VERSION 5.7 ;
  NOWIREEXTENSIONATPIN ON ;
  DIVIDERCHAR "/" ;
  BUSBITCHARS "[]" ;
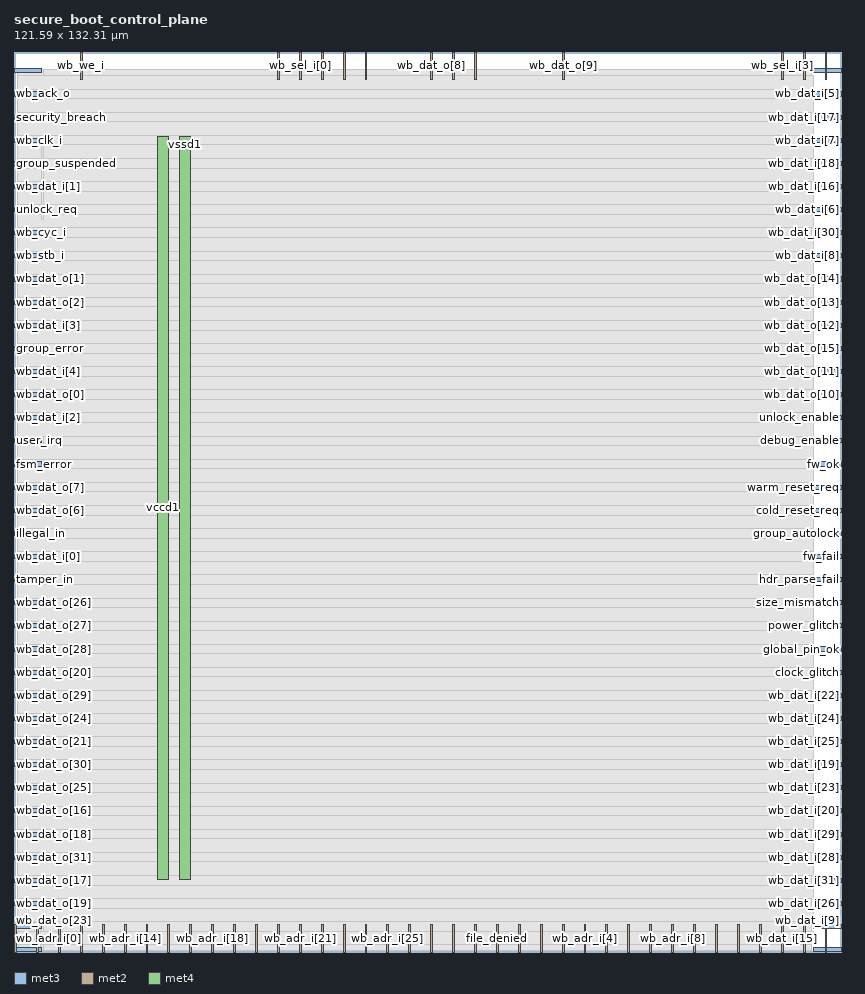
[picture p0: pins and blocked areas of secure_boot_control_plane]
MACRO secure_boot_control_plane
  CLASS BLOCK ;
  FOREIGN secure_boot_control_plane ;
  ORIGIN 0.000 0.000 ;
  SIZE 121.590 BY 132.310 ;
  PIN clock_glitch
    DIRECTION INPUT ;
    USE SIGNAL ;
    ANTENNAGATEAREA 0.631200 ;
    ANTENNADIFFAREA 0.434700 ;
    PORT
      LAYER met3 ;
        RECT 117.590 40.840 121.590 41.440 ;
    END
  END clock_glitch
  PIN cold_reset_req
    DIRECTION INPUT ;
    USE SIGNAL ;
    ANTENNAGATEAREA 0.631200 ;
    ANTENNADIFFAREA 0.434700 ;
    PORT
      LAYER met3 ;
        RECT 117.590 64.640 121.590 65.240 ;
    END
  END cold_reset_req
  PIN debug_enable
    DIRECTION OUTPUT ;
    USE SIGNAL ;
    ANTENNADIFFAREA 0.445500 ;
    PORT
      LAYER met3 ;
        RECT 117.590 74.840 121.590 75.440 ;
    END
  END debug_enable
  PIN file_denied
    DIRECTION INPUT ;
    USE SIGNAL ;
    ANTENNAGATEAREA 0.631200 ;
    ANTENNADIFFAREA 0.434700 ;
    PORT
      LAYER met2 ;
        RECT 70.930 0.000 71.210 4.000 ;
    END
  END file_denied
  PIN fsm_error
    DIRECTION OUTPUT ;
    USE SIGNAL ;
    ANTENNADIFFAREA 0.445500 ;
    PORT
      LAYER met3 ;
        RECT 0.000 71.440 4.000 72.040 ;
    END
  END fsm_error
  PIN fw_fail
    DIRECTION INPUT ;
    USE SIGNAL ;
    ANTENNAGATEAREA 0.631200 ;
    ANTENNADIFFAREA 0.434700 ;
    PORT
      LAYER met3 ;
        RECT 117.590 57.840 121.590 58.440 ;
    END
  END fw_fail
  PIN fw_ok
    DIRECTION INPUT ;
    USE SIGNAL ;
    ANTENNAGATEAREA 0.631200 ;
    ANTENNADIFFAREA 0.434700 ;
    PORT
      LAYER met3 ;
        RECT 117.590 71.440 121.590 72.040 ;
    END
  END fw_ok
  PIN global_pin_ok
    DIRECTION INPUT ;
    USE SIGNAL ;
    ANTENNAGATEAREA 0.631200 ;
    ANTENNADIFFAREA 0.434700 ;
    PORT
      LAYER met3 ;
        RECT 117.590 44.240 121.590 44.840 ;
    END
  END global_pin_ok
  PIN group_autolock
    DIRECTION INPUT ;
    USE SIGNAL ;
    ANTENNAGATEAREA 0.631200 ;
    ANTENNADIFFAREA 0.434700 ;
    PORT
      LAYER met3 ;
        RECT 117.590 61.240 121.590 61.840 ;
    END
  END group_autolock
  PIN group_error
    DIRECTION OUTPUT ;
    USE SIGNAL ;
    ANTENNADIFFAREA 0.445500 ;
    PORT
      LAYER met3 ;
        RECT 0.000 88.440 4.000 89.040 ;
    END
  END group_error
  PIN group_suspended
    DIRECTION OUTPUT ;
    USE SIGNAL ;
    ANTENNADIFFAREA 0.445500 ;
    PORT
      LAYER met3 ;
        RECT 0.000 115.640 4.000 116.240 ;
    END
  END group_suspended
  PIN group_unlocked
    DIRECTION OUTPUT ;
    USE SIGNAL ;
    ANTENNADIFFAREA 0.445500 ;
    PORT
      LAYER met2 ;
        RECT 67.710 0.000 67.990 4.000 ;
    END
  END group_unlocked
  PIN hdr_parse_fail
    DIRECTION INPUT ;
    USE SIGNAL ;
    ANTENNAGATEAREA 0.631200 ;
    ANTENNADIFFAREA 0.434700 ;
    PORT
      LAYER met3 ;
        RECT 117.590 54.440 121.590 55.040 ;
    END
  END hdr_parse_fail
  PIN illegal_in
    DIRECTION INPUT ;
    USE SIGNAL ;
    ANTENNAGATEAREA 0.631200 ;
    ANTENNADIFFAREA 0.434700 ;
    PORT
      LAYER met3 ;
        RECT 0.000 61.240 4.000 61.840 ;
    END
  END illegal_in
  PIN power_glitch
    DIRECTION INPUT ;
    USE SIGNAL ;
    ANTENNAGATEAREA 0.631200 ;
    ANTENNADIFFAREA 0.434700 ;
    PORT
      LAYER met3 ;
        RECT 117.590 47.640 121.590 48.240 ;
    END
  END power_glitch
  PIN safe_led
    DIRECTION OUTPUT ;
    USE SIGNAL ;
    ANTENNADIFFAREA 0.445500 ;
    PORT
      LAYER met2 ;
        RECT 64.490 128.310 64.770 132.310 ;
    END
  END safe_led
  PIN security_breach
    DIRECTION OUTPUT ;
    USE SIGNAL ;
    ANTENNADIFFAREA 0.445500 ;
    PORT
      LAYER met3 ;
        RECT 0.000 122.440 4.000 123.040 ;
    END
  END security_breach
  PIN size_mismatch
    DIRECTION INPUT ;
    USE SIGNAL ;
    ANTENNAGATEAREA 0.631200 ;
    ANTENNADIFFAREA 0.434700 ;
    PORT
      LAYER met3 ;
        RECT 117.590 51.040 121.590 51.640 ;
    END
  END size_mismatch
  PIN tamper_in
    DIRECTION INPUT ;
    USE SIGNAL ;
    ANTENNAGATEAREA 0.631200 ;
    ANTENNADIFFAREA 0.434700 ;
    PORT
      LAYER met3 ;
        RECT 0.000 54.440 4.000 55.040 ;
    END
  END tamper_in
  PIN unlock_enable
    DIRECTION OUTPUT ;
    USE SIGNAL ;
    ANTENNADIFFAREA 0.445500 ;
    PORT
      LAYER met3 ;
        RECT 117.590 78.240 121.590 78.840 ;
    END
  END unlock_enable
  PIN unlock_req
    DIRECTION INPUT ;
    USE SIGNAL ;
    ANTENNAGATEAREA 0.631200 ;
    ANTENNADIFFAREA 0.434700 ;
    PORT
      LAYER met3 ;
        RECT 0.000 108.840 4.000 109.440 ;
    END
  END unlock_req
  PIN user_irq
    DIRECTION OUTPUT ;
    USE SIGNAL ;
    ANTENNADIFFAREA 0.445500 ;
    PORT
      LAYER met3 ;
        RECT 0.000 74.840 4.000 75.440 ;
    END
  END user_irq
  PIN vccd1
    DIRECTION INOUT ;
    USE POWER ;
    PORT
      LAYER met4 ;
        RECT 21.040 10.640 22.640 119.920 ;
    END
  END vccd1
  PIN vssd1
    DIRECTION INOUT ;
    USE GROUND ;
    PORT
      LAYER met4 ;
        RECT 24.340 10.640 25.940 119.920 ;
    END
  END vssd1
  PIN warm_reset_req
    DIRECTION INPUT ;
    USE SIGNAL ;
    ANTENNAGATEAREA 0.560700 ;
    ANTENNADIFFAREA 0.434700 ;
    PORT
      LAYER met3 ;
        RECT 117.590 68.040 121.590 68.640 ;
    END
  END warm_reset_req
  PIN wb_ack_o
    DIRECTION OUTPUT ;
    USE SIGNAL ;
    ANTENNADIFFAREA 0.445500 ;
    PORT
      LAYER met3 ;
        RECT 0.000 125.840 4.000 126.440 ;
    END
  END wb_ack_o
  PIN wb_adr_i[0]
    DIRECTION INPUT ;
    USE SIGNAL ;
    PORT
      LAYER met2 ;
        RECT 0.090 0.000 0.370 4.000 ;
    END
  END wb_adr_i[0]
  PIN wb_adr_i[10]
    DIRECTION INPUT ;
    USE SIGNAL ;
    PORT
      LAYER met2 ;
        RECT 3.310 0.000 3.590 4.000 ;
    END
  END wb_adr_i[10]
  PIN wb_adr_i[11]
    DIRECTION INPUT ;
    USE SIGNAL ;
    PORT
      LAYER met2 ;
        RECT 6.530 0.000 6.810 4.000 ;
    END
  END wb_adr_i[11]
  PIN wb_adr_i[12]
    DIRECTION INPUT ;
    USE SIGNAL ;
    PORT
      LAYER met2 ;
        RECT 9.750 0.000 10.030 4.000 ;
    END
  END wb_adr_i[12]
  PIN wb_adr_i[13]
    DIRECTION INPUT ;
    USE SIGNAL ;
    PORT
      LAYER met2 ;
        RECT 12.970 0.000 13.250 4.000 ;
    END
  END wb_adr_i[13]
  PIN wb_adr_i[14]
    DIRECTION INPUT ;
    USE SIGNAL ;
    PORT
      LAYER met2 ;
        RECT 16.190 0.000 16.470 4.000 ;
    END
  END wb_adr_i[14]
  PIN wb_adr_i[15]
    DIRECTION INPUT ;
    USE SIGNAL ;
    PORT
      LAYER met2 ;
        RECT 19.410 0.000 19.690 4.000 ;
    END
  END wb_adr_i[15]
  PIN wb_adr_i[16]
    DIRECTION INPUT ;
    USE SIGNAL ;
    PORT
      LAYER met2 ;
        RECT 22.630 0.000 22.910 4.000 ;
    END
  END wb_adr_i[16]
  PIN wb_adr_i[17]
    DIRECTION INPUT ;
    USE SIGNAL ;
    PORT
      LAYER met2 ;
        RECT 25.850 0.000 26.130 4.000 ;
    END
  END wb_adr_i[17]
  PIN wb_adr_i[18]
    DIRECTION INPUT ;
    USE SIGNAL ;
    PORT
      LAYER met2 ;
        RECT 29.070 0.000 29.350 4.000 ;
    END
  END wb_adr_i[18]
  PIN wb_adr_i[19]
    DIRECTION INPUT ;
    USE SIGNAL ;
    PORT
      LAYER met2 ;
        RECT 32.290 0.000 32.570 4.000 ;
    END
  END wb_adr_i[19]
  PIN wb_adr_i[1]
    DIRECTION INPUT ;
    USE SIGNAL ;
    PORT
      LAYER met2 ;
        RECT 35.510 0.000 35.790 4.000 ;
    END
  END wb_adr_i[1]
  PIN wb_adr_i[20]
    DIRECTION INPUT ;
    USE SIGNAL ;
    PORT
      LAYER met2 ;
        RECT 38.730 0.000 39.010 4.000 ;
    END
  END wb_adr_i[20]
  PIN wb_adr_i[21]
    DIRECTION INPUT ;
    USE SIGNAL ;
    PORT
      LAYER met2 ;
        RECT 41.950 0.000 42.230 4.000 ;
    END
  END wb_adr_i[21]
  PIN wb_adr_i[22]
    DIRECTION INPUT ;
    USE SIGNAL ;
    PORT
      LAYER met2 ;
        RECT 45.170 0.000 45.450 4.000 ;
    END
  END wb_adr_i[22]
  PIN wb_adr_i[23]
    DIRECTION INPUT ;
    USE SIGNAL ;
    PORT
      LAYER met2 ;
        RECT 48.390 0.000 48.670 4.000 ;
    END
  END wb_adr_i[23]
  PIN wb_adr_i[24]
    DIRECTION INPUT ;
    USE SIGNAL ;
    PORT
      LAYER met2 ;
        RECT 51.610 0.000 51.890 4.000 ;
    END
  END wb_adr_i[24]
  PIN wb_adr_i[25]
    DIRECTION INPUT ;
    USE SIGNAL ;
    PORT
      LAYER met2 ;
        RECT 54.830 0.000 55.110 4.000 ;
    END
  END wb_adr_i[25]
  PIN wb_adr_i[26]
    DIRECTION INPUT ;
    USE SIGNAL ;
    PORT
      LAYER met2 ;
        RECT 58.050 0.000 58.330 4.000 ;
    END
  END wb_adr_i[26]
  PIN wb_adr_i[27]
    DIRECTION INPUT ;
    USE SIGNAL ;
    PORT
      LAYER met2 ;
        RECT 61.270 0.000 61.550 4.000 ;
    END
  END wb_adr_i[27]
  PIN wb_adr_i[28]
    DIRECTION INPUT ;
    USE SIGNAL ;
    PORT
      LAYER met2 ;
        RECT 64.490 0.000 64.770 4.000 ;
    END
  END wb_adr_i[28]
  PIN wb_adr_i[29]
    DIRECTION INPUT ;
    USE SIGNAL ;
    PORT
      LAYER met2 ;
        RECT 77.370 0.000 77.650 4.000 ;
    END
  END wb_adr_i[29]
  PIN wb_adr_i[2]
    DIRECTION INPUT ;
    USE SIGNAL ;
    ANTENNAGATEAREA 0.647700 ;
    ANTENNADIFFAREA 0.434700 ;
    PORT
      LAYER met2 ;
        RECT 48.390 128.310 48.670 132.310 ;
    END
  END wb_adr_i[2]
  PIN wb_adr_i[30]
    DIRECTION INPUT ;
    USE SIGNAL ;
    PORT
      LAYER met2 ;
        RECT 80.590 0.000 80.870 4.000 ;
    END
  END wb_adr_i[30]
  PIN wb_adr_i[31]
    DIRECTION INPUT ;
    USE SIGNAL ;
    PORT
      LAYER met2 ;
        RECT 74.150 0.000 74.430 4.000 ;
    END
  END wb_adr_i[31]
  PIN wb_adr_i[3]
    DIRECTION INPUT ;
    USE SIGNAL ;
    ANTENNAGATEAREA 0.593700 ;
    ANTENNADIFFAREA 0.434700 ;
    PORT
      LAYER met2 ;
        RECT 38.730 128.310 39.010 132.310 ;
    END
  END wb_adr_i[3]
  PIN wb_adr_i[4]
    DIRECTION INPUT ;
    USE SIGNAL ;
    PORT
      LAYER met2 ;
        RECT 83.810 0.000 84.090 4.000 ;
    END
  END wb_adr_i[4]
  PIN wb_adr_i[5]
    DIRECTION INPUT ;
    USE SIGNAL ;
    PORT
      LAYER met2 ;
        RECT 90.250 0.000 90.530 4.000 ;
    END
  END wb_adr_i[5]
  PIN wb_adr_i[6]
    DIRECTION INPUT ;
    USE SIGNAL ;
    PORT
      LAYER met2 ;
        RECT 93.470 0.000 93.750 4.000 ;
    END
  END wb_adr_i[6]
  PIN wb_adr_i[7]
    DIRECTION INPUT ;
    USE SIGNAL ;
    PORT
      LAYER met2 ;
        RECT 87.030 0.000 87.310 4.000 ;
    END
  END wb_adr_i[7]
  PIN wb_adr_i[8]
    DIRECTION INPUT ;
    USE SIGNAL ;
    PORT
      LAYER met2 ;
        RECT 96.690 0.000 96.970 4.000 ;
    END
  END wb_adr_i[8]
  PIN wb_adr_i[9]
    DIRECTION INPUT ;
    USE SIGNAL ;
    PORT
      LAYER met2 ;
        RECT 103.130 0.000 103.410 4.000 ;
    END
  END wb_adr_i[9]
  PIN wb_clk_i
    DIRECTION INPUT ;
    USE SIGNAL ;
    ANTENNAGATEAREA 1.286700 ;
    ANTENNADIFFAREA 0.434700 ;
    PORT
      LAYER met3 ;
        RECT 0.000 119.040 4.000 119.640 ;
    END
  END wb_clk_i
  PIN wb_cyc_i
    DIRECTION INPUT ;
    USE SIGNAL ;
    ANTENNAGATEAREA 0.631200 ;
    ANTENNADIFFAREA 0.434700 ;
    PORT
      LAYER met3 ;
        RECT 0.000 105.440 4.000 106.040 ;
    END
  END wb_cyc_i
  PIN wb_dat_i[0]
    DIRECTION INPUT ;
    USE SIGNAL ;
    ANTENNAGATEAREA 0.631200 ;
    ANTENNADIFFAREA 0.434700 ;
    PORT
      LAYER met3 ;
        RECT 0.000 57.840 4.000 58.440 ;
    END
  END wb_dat_i[0]
  PIN wb_dat_i[10]
    DIRECTION INPUT ;
    USE SIGNAL ;
    PORT
      LAYER met2 ;
        RECT 106.350 0.000 106.630 4.000 ;
    END
  END wb_dat_i[10]
  PIN wb_dat_i[11]
    DIRECTION INPUT ;
    USE SIGNAL ;
    PORT
      LAYER met2 ;
        RECT 99.910 0.000 100.190 4.000 ;
    END
  END wb_dat_i[11]
  PIN wb_dat_i[12]
    DIRECTION INPUT ;
    USE SIGNAL ;
    PORT
      LAYER met2 ;
        RECT 109.570 0.000 109.850 4.000 ;
    END
  END wb_dat_i[12]
  PIN wb_dat_i[13]
    DIRECTION INPUT ;
    USE SIGNAL ;
    PORT
      LAYER met2 ;
        RECT 116.010 0.000 116.290 4.000 ;
    END
  END wb_dat_i[13]
  PIN wb_dat_i[14]
    DIRECTION INPUT ;
    USE SIGNAL ;
    PORT
      LAYER met2 ;
        RECT 119.230 0.000 119.510 4.000 ;
    END
  END wb_dat_i[14]
  PIN wb_dat_i[15]
    DIRECTION INPUT ;
    USE SIGNAL ;
    PORT
      LAYER met2 ;
        RECT 112.790 0.000 113.070 4.000 ;
    END
  END wb_dat_i[15]
  PIN wb_dat_i[16]
    DIRECTION INPUT ;
    USE SIGNAL ;
    PORT
      LAYER met3 ;
        RECT 117.590 112.240 121.590 112.840 ;
    END
  END wb_dat_i[16]
  PIN wb_dat_i[17]
    DIRECTION INPUT ;
    USE SIGNAL ;
    PORT
      LAYER met3 ;
        RECT 117.590 122.440 121.590 123.040 ;
    END
  END wb_dat_i[17]
  PIN wb_dat_i[18]
    DIRECTION INPUT ;
    USE SIGNAL ;
    PORT
      LAYER met3 ;
        RECT 117.590 115.640 121.590 116.240 ;
    END
  END wb_dat_i[18]
  PIN wb_dat_i[19]
    DIRECTION INPUT ;
    USE SIGNAL ;
    PORT
      LAYER met3 ;
        RECT 117.590 27.240 121.590 27.840 ;
    END
  END wb_dat_i[19]
  PIN wb_dat_i[1]
    DIRECTION INPUT ;
    USE SIGNAL ;
    ANTENNAGATEAREA 0.631200 ;
    ANTENNADIFFAREA 0.434700 ;
    PORT
      LAYER met3 ;
        RECT 0.000 112.240 4.000 112.840 ;
    END
  END wb_dat_i[1]
  PIN wb_dat_i[20]
    DIRECTION INPUT ;
    USE SIGNAL ;
    PORT
      LAYER met3 ;
        RECT 117.590 20.440 121.590 21.040 ;
    END
  END wb_dat_i[20]
  PIN wb_dat_i[21]
    DIRECTION INPUT ;
    USE SIGNAL ;
    PORT
      LAYER met3 ;
        RECT 117.590 129.240 121.590 129.840 ;
    END
  END wb_dat_i[21]
  PIN wb_dat_i[22]
    DIRECTION INPUT ;
    USE SIGNAL ;
    PORT
      LAYER met3 ;
        RECT 117.590 37.440 121.590 38.040 ;
    END
  END wb_dat_i[22]
  PIN wb_dat_i[23]
    DIRECTION INPUT ;
    USE SIGNAL ;
    PORT
      LAYER met3 ;
        RECT 117.590 23.840 121.590 24.440 ;
    END
  END wb_dat_i[23]
  PIN wb_dat_i[24]
    DIRECTION INPUT ;
    USE SIGNAL ;
    PORT
      LAYER met3 ;
        RECT 117.590 34.040 121.590 34.640 ;
    END
  END wb_dat_i[24]
  PIN wb_dat_i[25]
    DIRECTION INPUT ;
    USE SIGNAL ;
    PORT
      LAYER met3 ;
        RECT 117.590 30.640 121.590 31.240 ;
    END
  END wb_dat_i[25]
  PIN wb_dat_i[26]
    DIRECTION INPUT ;
    USE SIGNAL ;
    PORT
      LAYER met3 ;
        RECT 117.590 6.840 121.590 7.440 ;
    END
  END wb_dat_i[26]
  PIN wb_dat_i[27]
    DIRECTION INPUT ;
    USE SIGNAL ;
    PORT
      LAYER met3 ;
        RECT 117.590 0.040 121.590 0.640 ;
    END
  END wb_dat_i[27]
  PIN wb_dat_i[28]
    DIRECTION INPUT ;
    USE SIGNAL ;
    PORT
      LAYER met3 ;
        RECT 117.590 13.640 121.590 14.240 ;
    END
  END wb_dat_i[28]
  PIN wb_dat_i[29]
    DIRECTION INPUT ;
    USE SIGNAL ;
    PORT
      LAYER met3 ;
        RECT 117.590 17.040 121.590 17.640 ;
    END
  END wb_dat_i[29]
  PIN wb_dat_i[2]
    DIRECTION INPUT ;
    USE SIGNAL ;
    ANTENNAGATEAREA 0.631200 ;
    ANTENNADIFFAREA 0.434700 ;
    PORT
      LAYER met3 ;
        RECT 0.000 78.240 4.000 78.840 ;
    END
  END wb_dat_i[2]
  PIN wb_dat_i[30]
    DIRECTION INPUT ;
    USE SIGNAL ;
    PORT
      LAYER met3 ;
        RECT 117.590 105.440 121.590 106.040 ;
    END
  END wb_dat_i[30]
  PIN wb_dat_i[31]
    DIRECTION INPUT ;
    USE SIGNAL ;
    PORT
      LAYER met3 ;
        RECT 117.590 10.240 121.590 10.840 ;
    END
  END wb_dat_i[31]
  PIN wb_dat_i[3]
    DIRECTION INPUT ;
    USE SIGNAL ;
    ANTENNAGATEAREA 0.631200 ;
    ANTENNADIFFAREA 0.434700 ;
    PORT
      LAYER met3 ;
        RECT 0.000 91.840 4.000 92.440 ;
    END
  END wb_dat_i[3]
  PIN wb_dat_i[4]
    DIRECTION INPUT ;
    USE SIGNAL ;
    ANTENNAGATEAREA 0.631200 ;
    ANTENNADIFFAREA 0.434700 ;
    PORT
      LAYER met3 ;
        RECT 0.000 85.040 4.000 85.640 ;
    END
  END wb_dat_i[4]
  PIN wb_dat_i[5]
    DIRECTION INPUT ;
    USE SIGNAL ;
    PORT
      LAYER met3 ;
        RECT 117.590 125.840 121.590 126.440 ;
    END
  END wb_dat_i[5]
  PIN wb_dat_i[6]
    DIRECTION INPUT ;
    USE SIGNAL ;
    PORT
      LAYER met3 ;
        RECT 117.590 108.840 121.590 109.440 ;
    END
  END wb_dat_i[6]
  PIN wb_dat_i[7]
    DIRECTION INPUT ;
    USE SIGNAL ;
    PORT
      LAYER met3 ;
        RECT 117.590 119.040 121.590 119.640 ;
    END
  END wb_dat_i[7]
  PIN wb_dat_i[8]
    DIRECTION INPUT ;
    USE SIGNAL ;
    PORT
      LAYER met3 ;
        RECT 117.590 102.040 121.590 102.640 ;
    END
  END wb_dat_i[8]
  PIN wb_dat_i[9]
    DIRECTION INPUT ;
    USE SIGNAL ;
    PORT
      LAYER met3 ;
        RECT 117.590 3.440 121.590 4.040 ;
    END
  END wb_dat_i[9]
  PIN wb_dat_o[0]
    DIRECTION OUTPUT ;
    USE SIGNAL ;
    ANTENNADIFFAREA 0.445500 ;
    PORT
      LAYER met3 ;
        RECT 0.000 81.640 4.000 82.240 ;
    END
  END wb_dat_o[0]
  PIN wb_dat_o[10]
    DIRECTION OUTPUT ;
    USE SIGNAL ;
    ANTENNADIFFAREA 0.445500 ;
    PORT
      LAYER met3 ;
        RECT 117.590 81.640 121.590 82.240 ;
    END
  END wb_dat_o[10]
  PIN wb_dat_o[11]
    DIRECTION OUTPUT ;
    USE SIGNAL ;
    ANTENNADIFFAREA 0.445500 ;
    PORT
      LAYER met3 ;
        RECT 117.590 85.040 121.590 85.640 ;
    END
  END wb_dat_o[11]
  PIN wb_dat_o[12]
    DIRECTION OUTPUT ;
    USE SIGNAL ;
    ANTENNADIFFAREA 0.445500 ;
    PORT
      LAYER met3 ;
        RECT 117.590 91.840 121.590 92.440 ;
    END
  END wb_dat_o[12]
  PIN wb_dat_o[13]
    DIRECTION OUTPUT ;
    USE SIGNAL ;
    ANTENNADIFFAREA 0.445500 ;
    PORT
      LAYER met3 ;
        RECT 117.590 95.240 121.590 95.840 ;
    END
  END wb_dat_o[13]
  PIN wb_dat_o[14]
    DIRECTION OUTPUT ;
    USE SIGNAL ;
    ANTENNADIFFAREA 0.445500 ;
    PORT
      LAYER met3 ;
        RECT 117.590 98.640 121.590 99.240 ;
    END
  END wb_dat_o[14]
  PIN wb_dat_o[15]
    DIRECTION OUTPUT ;
    USE SIGNAL ;
    ANTENNADIFFAREA 0.445500 ;
    PORT
      LAYER met3 ;
        RECT 117.590 88.440 121.590 89.040 ;
    END
  END wb_dat_o[15]
  PIN wb_dat_o[16]
    DIRECTION OUTPUT ;
    USE SIGNAL ;
    ANTENNADIFFAREA 0.445500 ;
    PORT
      LAYER met3 ;
        RECT 0.000 20.440 4.000 21.040 ;
    END
  END wb_dat_o[16]
  PIN wb_dat_o[17]
    DIRECTION OUTPUT ;
    USE SIGNAL ;
    ANTENNADIFFAREA 0.445500 ;
    PORT
      LAYER met3 ;
        RECT 0.000 10.240 4.000 10.840 ;
    END
  END wb_dat_o[17]
  PIN wb_dat_o[18]
    DIRECTION OUTPUT ;
    USE SIGNAL ;
    ANTENNADIFFAREA 0.445500 ;
    PORT
      LAYER met3 ;
        RECT 0.000 17.040 4.000 17.640 ;
    END
  END wb_dat_o[18]
  PIN wb_dat_o[19]
    DIRECTION OUTPUT ;
    USE SIGNAL ;
    ANTENNADIFFAREA 0.445500 ;
    PORT
      LAYER met3 ;
        RECT 0.000 6.840 4.000 7.440 ;
    END
  END wb_dat_o[19]
  PIN wb_dat_o[1]
    DIRECTION OUTPUT ;
    USE SIGNAL ;
    ANTENNADIFFAREA 0.445500 ;
    PORT
      LAYER met3 ;
        RECT 0.000 98.640 4.000 99.240 ;
    END
  END wb_dat_o[1]
  PIN wb_dat_o[20]
    DIRECTION OUTPUT ;
    USE SIGNAL ;
    ANTENNADIFFAREA 0.445500 ;
    PORT
      LAYER met3 ;
        RECT 0.000 40.840 4.000 41.440 ;
    END
  END wb_dat_o[20]
  PIN wb_dat_o[21]
    DIRECTION OUTPUT ;
    USE SIGNAL ;
    ANTENNADIFFAREA 0.445500 ;
    PORT
      LAYER met3 ;
        RECT 0.000 30.640 4.000 31.240 ;
    END
  END wb_dat_o[21]
  PIN wb_dat_o[22]
    DIRECTION OUTPUT ;
    USE SIGNAL ;
    ANTENNADIFFAREA 0.445500 ;
    PORT
      LAYER met3 ;
        RECT 0.000 0.040 4.000 0.640 ;
    END
  END wb_dat_o[22]
  PIN wb_dat_o[23]
    DIRECTION OUTPUT ;
    USE SIGNAL ;
    ANTENNADIFFAREA 0.445500 ;
    PORT
      LAYER met3 ;
        RECT 0.000 3.440 4.000 4.040 ;
    END
  END wb_dat_o[23]
  PIN wb_dat_o[24]
    DIRECTION OUTPUT ;
    USE SIGNAL ;
    ANTENNADIFFAREA 0.445500 ;
    PORT
      LAYER met3 ;
        RECT 0.000 34.040 4.000 34.640 ;
    END
  END wb_dat_o[24]
  PIN wb_dat_o[25]
    DIRECTION OUTPUT ;
    USE SIGNAL ;
    ANTENNADIFFAREA 0.445500 ;
    PORT
      LAYER met3 ;
        RECT 0.000 23.840 4.000 24.440 ;
    END
  END wb_dat_o[25]
  PIN wb_dat_o[26]
    DIRECTION OUTPUT ;
    USE SIGNAL ;
    ANTENNADIFFAREA 0.445500 ;
    PORT
      LAYER met3 ;
        RECT 0.000 51.040 4.000 51.640 ;
    END
  END wb_dat_o[26]
  PIN wb_dat_o[27]
    DIRECTION OUTPUT ;
    USE SIGNAL ;
    ANTENNADIFFAREA 0.445500 ;
    PORT
      LAYER met3 ;
        RECT 0.000 47.640 4.000 48.240 ;
    END
  END wb_dat_o[27]
  PIN wb_dat_o[28]
    DIRECTION OUTPUT ;
    USE SIGNAL ;
    ANTENNADIFFAREA 0.445500 ;
    PORT
      LAYER met3 ;
        RECT 0.000 44.240 4.000 44.840 ;
    END
  END wb_dat_o[28]
  PIN wb_dat_o[29]
    DIRECTION OUTPUT ;
    USE SIGNAL ;
    ANTENNADIFFAREA 0.445500 ;
    PORT
      LAYER met3 ;
        RECT 0.000 37.440 4.000 38.040 ;
    END
  END wb_dat_o[29]
  PIN wb_dat_o[2]
    DIRECTION OUTPUT ;
    USE SIGNAL ;
    ANTENNADIFFAREA 0.445500 ;
    PORT
      LAYER met3 ;
        RECT 0.000 95.240 4.000 95.840 ;
    END
  END wb_dat_o[2]
  PIN wb_dat_o[30]
    DIRECTION OUTPUT ;
    USE SIGNAL ;
    ANTENNADIFFAREA 0.445500 ;
    PORT
      LAYER met3 ;
        RECT 0.000 27.240 4.000 27.840 ;
    END
  END wb_dat_o[30]
  PIN wb_dat_o[31]
    DIRECTION OUTPUT ;
    USE SIGNAL ;
    ANTENNADIFFAREA 0.445500 ;
    PORT
      LAYER met3 ;
        RECT 0.000 13.640 4.000 14.240 ;
    END
  END wb_dat_o[31]
  PIN wb_dat_o[3]
    DIRECTION OUTPUT ;
    USE SIGNAL ;
    ANTENNADIFFAREA 0.445500 ;
    PORT
      LAYER met2 ;
        RECT 45.170 128.310 45.450 132.310 ;
    END
  END wb_dat_o[3]
  PIN wb_dat_o[4]
    DIRECTION OUTPUT ;
    USE SIGNAL ;
    ANTENNADIFFAREA 0.445500 ;
    PORT
      LAYER met2 ;
        RECT 67.710 128.310 67.990 132.310 ;
    END
  END wb_dat_o[4]
  PIN wb_dat_o[5]
    DIRECTION OUTPUT ;
    USE SIGNAL ;
    ANTENNADIFFAREA 0.445500 ;
    PORT
      LAYER met2 ;
        RECT 51.610 128.310 51.890 132.310 ;
    END
  END wb_dat_o[5]
  PIN wb_dat_o[6]
    DIRECTION OUTPUT ;
    USE SIGNAL ;
    ANTENNADIFFAREA 0.445500 ;
    PORT
      LAYER met3 ;
        RECT 0.000 64.640 4.000 65.240 ;
    END
  END wb_dat_o[6]
  PIN wb_dat_o[7]
    DIRECTION OUTPUT ;
    USE SIGNAL ;
    ANTENNADIFFAREA 0.445500 ;
    PORT
      LAYER met3 ;
        RECT 0.000 68.040 4.000 68.640 ;
    END
  END wb_dat_o[7]
  PIN wb_dat_o[8]
    DIRECTION OUTPUT ;
    USE SIGNAL ;
    ANTENNADIFFAREA 0.445500 ;
    PORT
      LAYER met2 ;
        RECT 61.270 128.310 61.550 132.310 ;
    END
  END wb_dat_o[8]
  PIN wb_dat_o[9]
    DIRECTION OUTPUT ;
    USE SIGNAL ;
    ANTENNADIFFAREA 0.445500 ;
    PORT
      LAYER met2 ;
        RECT 80.590 128.310 80.870 132.310 ;
    END
  END wb_dat_o[9]
  PIN wb_rst_i
    DIRECTION INPUT ;
    USE SIGNAL ;
    ANTENNAGATEAREA 0.631200 ;
    ANTENNADIFFAREA 0.434700 ;
    PORT
      LAYER met3 ;
        RECT 0.000 129.240 4.000 129.840 ;
    END
  END wb_rst_i
  PIN wb_sel_i[0]
    DIRECTION INPUT ;
    USE SIGNAL ;
    ANTENNAGATEAREA 0.631200 ;
    ANTENNADIFFAREA 0.434700 ;
    PORT
      LAYER met2 ;
        RECT 41.950 128.310 42.230 132.310 ;
    END
  END wb_sel_i[0]
  PIN wb_sel_i[1]
    DIRECTION INPUT ;
    USE SIGNAL ;
    PORT
      LAYER met2 ;
        RECT 119.230 128.310 119.510 132.310 ;
    END
  END wb_sel_i[1]
  PIN wb_sel_i[2]
    DIRECTION INPUT ;
    USE SIGNAL ;
    PORT
      LAYER met2 ;
        RECT 116.010 128.310 116.290 132.310 ;
    END
  END wb_sel_i[2]
  PIN wb_sel_i[3]
    DIRECTION INPUT ;
    USE SIGNAL ;
    PORT
      LAYER met2 ;
        RECT 112.790 128.310 113.070 132.310 ;
    END
  END wb_sel_i[3]
  PIN wb_stb_i
    DIRECTION INPUT ;
    USE SIGNAL ;
    ANTENNAGATEAREA 0.631200 ;
    ANTENNADIFFAREA 0.434700 ;
    PORT
      LAYER met3 ;
        RECT 0.000 102.040 4.000 102.640 ;
    END
  END wb_stb_i
  PIN wb_we_i
    DIRECTION INPUT ;
    USE SIGNAL ;
    ANTENNAGATEAREA 0.631200 ;
    ANTENNADIFFAREA 0.434700 ;
    PORT
      LAYER met2 ;
        RECT 9.750 128.310 10.030 132.310 ;
    END
  END wb_we_i
  OBS
      LAYER nwell ;
        RECT 5.330 10.795 116.110 119.765 ;
      LAYER li1 ;
        RECT 5.520 10.795 115.920 119.765 ;
      LAYER met1 ;
        RECT 0.530 10.640 115.920 119.920 ;
      LAYER met2 ;
        RECT 0.550 128.030 9.470 129.725 ;
        RECT 10.310 128.030 38.450 129.725 ;
        RECT 39.290 128.030 41.670 129.725 ;
        RECT 42.510 128.030 44.890 129.725 ;
        RECT 45.730 128.030 48.110 129.725 ;
        RECT 48.950 128.030 51.330 129.725 ;
        RECT 52.170 128.030 60.990 129.725 ;
        RECT 61.830 128.030 64.210 129.725 ;
        RECT 65.050 128.030 67.430 129.725 ;
        RECT 68.270 128.030 80.310 129.725 ;
        RECT 81.150 128.030 112.510 129.725 ;
        RECT 113.350 128.030 114.450 129.725 ;
        RECT 0.550 4.280 114.450 128.030 ;
        RECT 0.650 0.155 3.030 4.280 ;
        RECT 3.870 0.155 6.250 4.280 ;
        RECT 7.090 0.155 9.470 4.280 ;
        RECT 10.310 0.155 12.690 4.280 ;
        RECT 13.530 0.155 15.910 4.280 ;
        RECT 16.750 0.155 19.130 4.280 ;
        RECT 19.970 0.155 22.350 4.280 ;
        RECT 23.190 0.155 25.570 4.280 ;
        RECT 26.410 0.155 28.790 4.280 ;
        RECT 29.630 0.155 32.010 4.280 ;
        RECT 32.850 0.155 35.230 4.280 ;
        RECT 36.070 0.155 38.450 4.280 ;
        RECT 39.290 0.155 41.670 4.280 ;
        RECT 42.510 0.155 44.890 4.280 ;
        RECT 45.730 0.155 48.110 4.280 ;
        RECT 48.950 0.155 51.330 4.280 ;
        RECT 52.170 0.155 54.550 4.280 ;
        RECT 55.390 0.155 57.770 4.280 ;
        RECT 58.610 0.155 60.990 4.280 ;
        RECT 61.830 0.155 64.210 4.280 ;
        RECT 65.050 0.155 67.430 4.280 ;
        RECT 68.270 0.155 70.650 4.280 ;
        RECT 71.490 0.155 73.870 4.280 ;
        RECT 74.710 0.155 77.090 4.280 ;
        RECT 77.930 0.155 80.310 4.280 ;
        RECT 81.150 0.155 83.530 4.280 ;
        RECT 84.370 0.155 86.750 4.280 ;
        RECT 87.590 0.155 89.970 4.280 ;
        RECT 90.810 0.155 93.190 4.280 ;
        RECT 94.030 0.155 96.410 4.280 ;
        RECT 97.250 0.155 99.630 4.280 ;
        RECT 100.470 0.155 102.850 4.280 ;
        RECT 103.690 0.155 106.070 4.280 ;
        RECT 106.910 0.155 109.290 4.280 ;
        RECT 110.130 0.155 112.510 4.280 ;
        RECT 113.350 0.155 114.450 4.280 ;
      LAYER met3 ;
        RECT 4.400 128.840 117.190 129.705 ;
        RECT 0.525 126.840 117.590 128.840 ;
        RECT 4.400 125.440 117.190 126.840 ;
        RECT 0.525 123.440 117.590 125.440 ;
        RECT 4.400 122.040 117.190 123.440 ;
        RECT 0.525 120.040 117.590 122.040 ;
        RECT 4.400 118.640 117.190 120.040 ;
        RECT 0.525 116.640 117.590 118.640 ;
        RECT 4.400 115.240 117.190 116.640 ;
        RECT 0.525 113.240 117.590 115.240 ;
        RECT 4.400 111.840 117.190 113.240 ;
        RECT 0.525 109.840 117.590 111.840 ;
        RECT 4.400 108.440 117.190 109.840 ;
        RECT 0.525 106.440 117.590 108.440 ;
        RECT 4.400 105.040 117.190 106.440 ;
        RECT 0.525 103.040 117.590 105.040 ;
        RECT 4.400 101.640 117.190 103.040 ;
        RECT 0.525 99.640 117.590 101.640 ;
        RECT 4.400 98.240 117.190 99.640 ;
        RECT 0.525 96.240 117.590 98.240 ;
        RECT 4.400 94.840 117.190 96.240 ;
        RECT 0.525 92.840 117.590 94.840 ;
        RECT 4.400 91.440 117.190 92.840 ;
        RECT 0.525 89.440 117.590 91.440 ;
        RECT 4.400 88.040 117.190 89.440 ;
        RECT 0.525 86.040 117.590 88.040 ;
        RECT 4.400 84.640 117.190 86.040 ;
        RECT 0.525 82.640 117.590 84.640 ;
        RECT 4.400 81.240 117.190 82.640 ;
        RECT 0.525 79.240 117.590 81.240 ;
        RECT 4.400 77.840 117.190 79.240 ;
        RECT 0.525 75.840 117.590 77.840 ;
        RECT 4.400 74.440 117.190 75.840 ;
        RECT 0.525 72.440 117.590 74.440 ;
        RECT 4.400 71.040 117.190 72.440 ;
        RECT 0.525 69.040 117.590 71.040 ;
        RECT 4.400 67.640 117.190 69.040 ;
        RECT 0.525 65.640 117.590 67.640 ;
        RECT 4.400 64.240 117.190 65.640 ;
        RECT 0.525 62.240 117.590 64.240 ;
        RECT 4.400 60.840 117.190 62.240 ;
        RECT 0.525 58.840 117.590 60.840 ;
        RECT 4.400 57.440 117.190 58.840 ;
        RECT 0.525 55.440 117.590 57.440 ;
        RECT 4.400 54.040 117.190 55.440 ;
        RECT 0.525 52.040 117.590 54.040 ;
        RECT 4.400 50.640 117.190 52.040 ;
        RECT 0.525 48.640 117.590 50.640 ;
        RECT 4.400 47.240 117.190 48.640 ;
        RECT 0.525 45.240 117.590 47.240 ;
        RECT 4.400 43.840 117.190 45.240 ;
        RECT 0.525 41.840 117.590 43.840 ;
        RECT 4.400 40.440 117.190 41.840 ;
        RECT 0.525 38.440 117.590 40.440 ;
        RECT 4.400 37.040 117.190 38.440 ;
        RECT 0.525 35.040 117.590 37.040 ;
        RECT 4.400 33.640 117.190 35.040 ;
        RECT 0.525 31.640 117.590 33.640 ;
        RECT 4.400 30.240 117.190 31.640 ;
        RECT 0.525 28.240 117.590 30.240 ;
        RECT 4.400 26.840 117.190 28.240 ;
        RECT 0.525 24.840 117.590 26.840 ;
        RECT 4.400 23.440 117.190 24.840 ;
        RECT 0.525 21.440 117.590 23.440 ;
        RECT 4.400 20.040 117.190 21.440 ;
        RECT 0.525 18.040 117.590 20.040 ;
        RECT 4.400 16.640 117.190 18.040 ;
        RECT 0.525 14.640 117.590 16.640 ;
        RECT 4.400 13.240 117.190 14.640 ;
        RECT 0.525 11.240 117.590 13.240 ;
        RECT 4.400 9.840 117.190 11.240 ;
        RECT 0.525 7.840 117.590 9.840 ;
        RECT 4.400 6.440 117.190 7.840 ;
        RECT 0.525 4.440 117.590 6.440 ;
        RECT 4.400 3.040 117.190 4.440 ;
        RECT 0.525 1.040 117.590 3.040 ;
        RECT 4.400 0.175 117.190 1.040 ;
      LAYER met4 ;
        RECT 3.975 107.615 4.305 119.505 ;
  END
END secure_boot_control_plane
END LIBRARY

